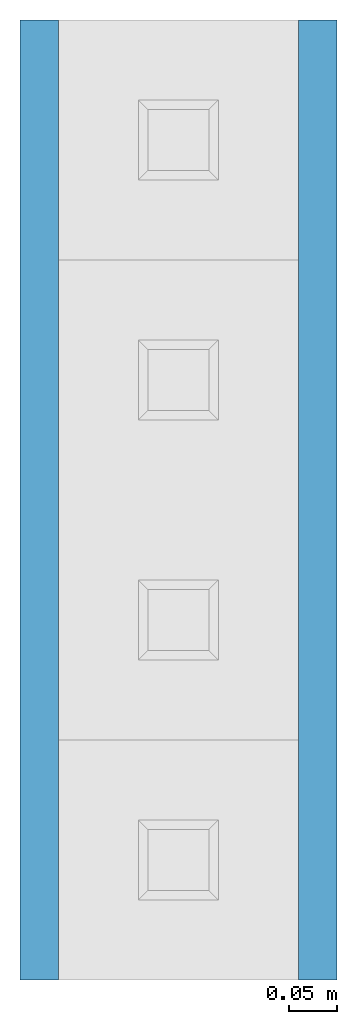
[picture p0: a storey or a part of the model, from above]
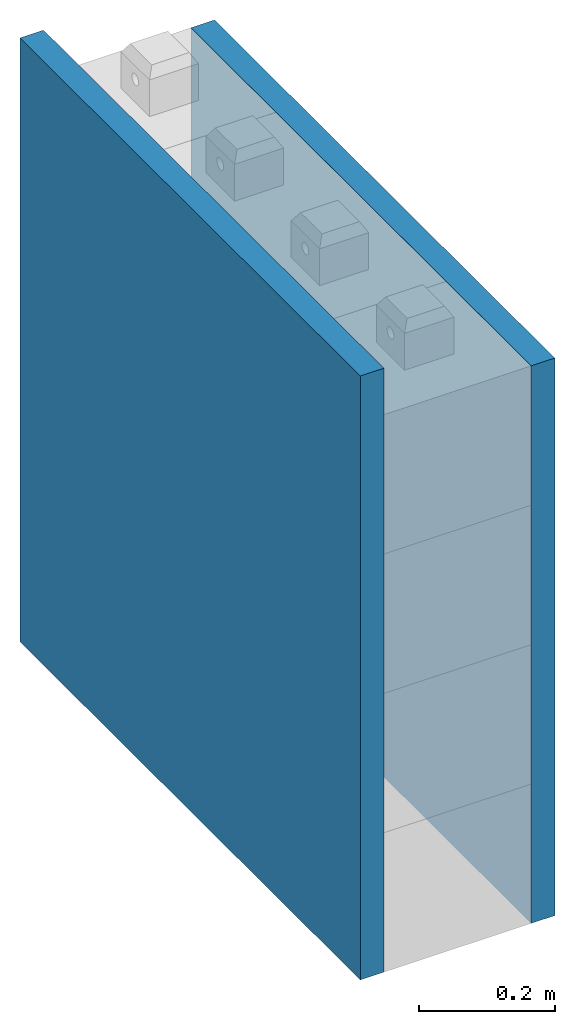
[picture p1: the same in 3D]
Properties of the parts of a building model (IFC4)

# File
Description: ViewDefinition [ReferenceView_V1.2], RevitIdentifiers [ContentGUID: d45b1106-0c7a-46e1-869b-c6a7bbcc7ea5, VersionGUID: 118b0530-1591-4ac2-8939-a10ffb714872, NumberOfSaves: 70], CoordinateReference [CoordinateBase: Internal Origin, ProjectSite: Internal], ExchangeRequirement [Architecture]
File name: 3dv__Detail__15__108, WS25 Wall, Feuerwiderstand Doppel Beplankt REI90.ifc
Time: 2025-12-19T14:27:38+01:00
Written by: ODA SDAI 25.12
Made in: Autodesk - Revit 26.3.0.37 (ENU) - 26.4.1.0

# IfcSite, Default
RefLatitude: 45, 45, 37, 23925; RefLongitude: 21, 14, 26, 780090; RefElevation: 0 cm

# IfcBuildingStorey (10)
Name | LongName | Elevation (cm)
B2__ABOVE Slab | B2__ABOVE Slab | -612
B1__ABOVE Slab | B1__ABOVE Slab | -312
L00__ABOVE Slab | L00__ABOVE Slab | -12
L01__ABOVE Slab | L01__ABOVE Slab | 273
L02__ABOVE Slab | L02__ABOVE Slab | 558
L03__ABOVE Slab | L03__ABOVE Slab | 843
L04__ABOVE Slab | L04__ABOVE Slab | 1128
L05__ABOVE Slab | L05__ABOVE Slab | 1413
L06__ABOVE Slab | L06__ABOVE Slab | 1698
L07__ABOVE Slab | L07__ABOVE Slab | 1983

# IfcColumn: Columns : wll__TIMBER CORE__Triqbriq__lb : WS25
In: L00__ABOVE Slab
Type - PredefinedType: COLUMN; Material: <Unnamed>

# IfcColumn: Columns : wll_s__TIMBER BLOCK__Triqbriq, Full Width__wp : WS25 (6)
In: L00__ABOVE Slab
Type - PredefinedType: COLUMN; Material: _MASONRY__Timber Block__Triqbriq, X, _MASONRY__Timber Block__Triqbriq, Y

# IfcColumn: Columns : wll_s__TIMBER BLOCK__Triqbriq, Half Width__wp : WS25 (4)
In: L00__ABOVE Slab
Type - PredefinedType: COLUMN; Material: _MASONRY__Timber Block__Triqbriq, X, _MASONRY__Timber Block__Triqbriq, Y

# IfcWall: Walls : Basic Wall : wll__INT COVERING__GB, GYP Adhesive 2cm__20(H2) 3 (2)
In: L00__ABOVE Slab
Type - PredefinedType: STANDARD
Classification: A 5.2.1.2 Tencuieli uscate gips-carton, placi cu cerinte de rezistenta la umiditate (Uniformat); Material: _PB__GB__Fire Resistant__Type DF
